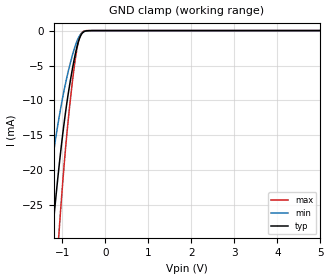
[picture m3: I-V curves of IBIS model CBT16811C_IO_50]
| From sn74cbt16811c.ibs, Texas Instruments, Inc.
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[Model]   CBT16811C_IO_50
Model_type  Terminator
| variable   typ   min   max
C_comp   5.77pF   4.37pF   8.32pF
| C_tri-state   5.77pF   4.37pF   8.32pF
[Temperature Range]   40   100   -40
| Ambient temperature   25   85   -40
[Voltage range]   5   4.5   5.5
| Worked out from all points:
|   GND clamp passes 1 mA (typ) near -0.59 V on its own axis
[GND Clamp]
| CBT16811C_IO_50
|   Voltage   I(typ)   I(min)   I(max)
-5V       -402.2mA   -300.9mA   -511.8mA
-1.455V   -45.58mA   -29.39mA   -67.35mA
-1.43V    -43.65mA   -28.12mA   -64.62mA
-1.22V    -28.62mA   -18.31mA   -42.73mA
-1.075V   -19.63mA   -12.57mA   -29.14mA
-905mV    -10.99mA   -7.102mA   -15.78mA
-825mV    -7.763mA   -5.016mA   -10.81mA
-735mV    -4.616mA   -2.97mA    -5.968mA
-680mV    -2.974mA   -1.921mA   -3.513mA
-615mV    -1.454mA   -971.3uA   -1.408mA
-495mV    -166.4uA   -143.2uA   -77.2uA
5V        570.8pA    1.883nA    133.3pA
